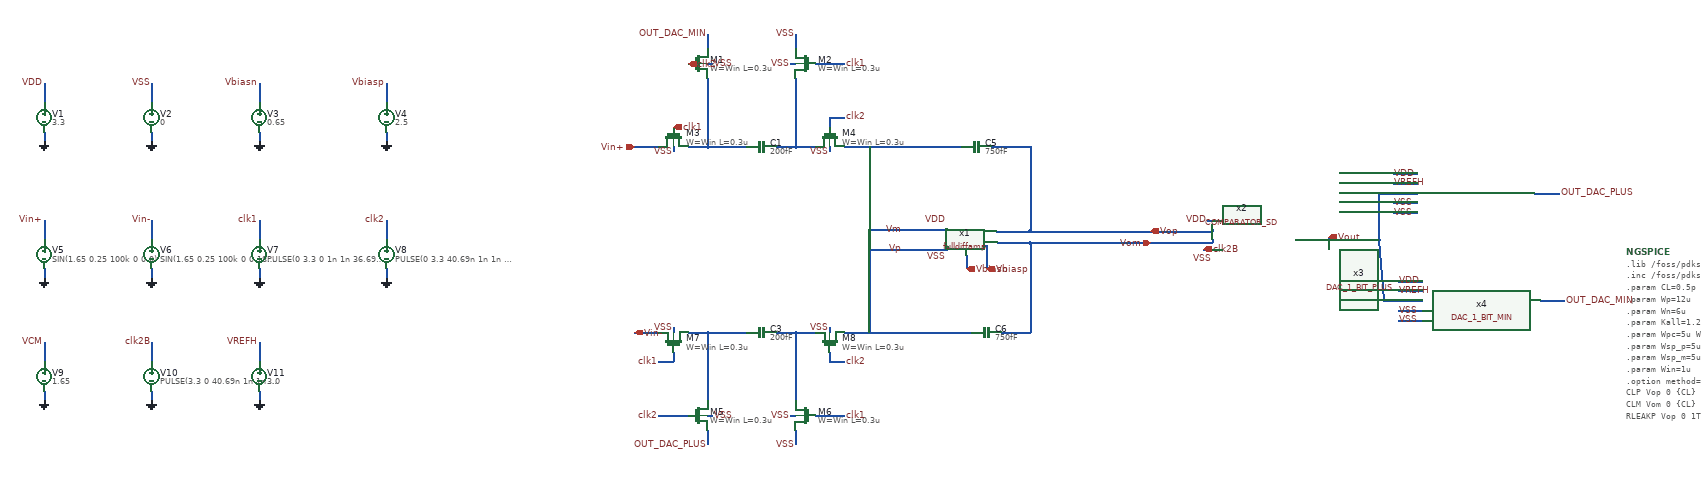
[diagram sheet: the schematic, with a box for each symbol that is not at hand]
v {xschem version=3.4.8RC file_version=1.3}
G {}
K {}
V {}
S {}
F {}
E {}
N -80 -1151.25 -80 -1011.25 {lab=#net1}
N -120 -1011.25 -80 -1011.25 {lab=#net1}
N -80 -1011.25 0 -1011.25 {lab=#net1}
N 60 -1011.25 100 -1011.25 {lab=#net2}
N 100 -1151.25 100 -1011.25 {lab=#net2}
N 100 -1011.25 140 -1011.25 {lab=#net2}
N 200 -1011.25 240 -1011.25 {lab=Vm}
N -200 -1011.25 -180 -1011.25 {lab=Vin+}
N -230 -1011.25 -200 -1011.25 {lab=Vin+}
N 170 -1071.25 170 -1051.25 {lab=clk2}
N 170 -1071.25 200 -1071.25 {lab=clk2}
N 140 -1181.25 200 -1181.25 {lab=clk1}
N 100 -1241.25 100 -1211.25 {lab=VSS}
N -80 -1241.25 -80 -1211.25 {lab=OUT_DAC_MIN}
N -80 -631.25 -80 -491.25 {lab=#net3}
N -120 -631.25 -80 -631.25 {lab=#net3}
N -80 -631.25 0 -631.25 {lab=#net3}
N 60 -631.25 100 -631.25 {lab=#net4}
N 100 -631.25 100 -491.25 {lab=#net4}
N 100 -631.25 140 -631.25 {lab=#net4}
N 200 -631.25 240 -631.25 {lab=Vp}
N -200 -631.25 -180 -631.25 {lab=Vin-}
N -230 -631.25 -200 -631.25 {lab=Vin-}
N -150 -591.25 -150 -571.25 {lab=clk1}
N -180 -571.25 -150 -571.25 {lab=clk1}
N -180 -461.25 -120 -461.25 {lab=clk2}
N 170 -591.25 170 -571.25 {lab=clk2}
N 170 -571.25 200 -571.25 {lab=clk2}
N 140 -461.25 200 -461.25 {lab=clk1}
N 100 -431.25 100 -401.25 {lab=VSS}
N -80 -431.25 -80 -401.25 {lab=OUT_DAC_PLUS}
N -80 -1181.25 -70 -1181.25 {lab=VSS}
N 90 -1181.25 100 -1181.25 {lab=VSS}
N -150 -1011.25 -150 -1001.25 {lab=VSS}
N 170 -1011.25 170 -1001.25 {lab=VSS}
N -150 -641.25 -150 -631.25 {lab=VSS}
N 170 -641.25 170 -631.25 {lab=VSS}
N -80 -461.25 -70 -461.25 {lab=VSS}
N 90 -461.25 100 -461.25 {lab=VSS}
N 240 -1011.25 440 -1011.25 {lab=Vm}
N 240 -631.25 460 -631.25 {lab=Vp}
N 250 -1011.25 250 -841.25 {lab=Vm}
N 250 -841.25 410 -841.25 {lab=Vm}
N 250 -801.25 250 -631.25 {lab=Vp}
N 250 -801.25 410 -801.25 {lab=Vp}
N 410 -806.25 410 -801.25 {lab=Vp}
N 500 -1011.25 570 -1011.25 {lab=Vop}
N 520 -631.25 580 -631.25 {lab=Vom}
N 512.5 -815 580 -815 {lab=Vom}
N 511.25 -838.75 578.75 -838.75 {lab=Vop}
N 570 -1011.25 580 -1011.25 {lab=Vop}
N 578.75 -838.75 580 -838.75 {lab=Vop}
N 580 -1011.25 580 -838.75 {lab=Vop}
N 580 -815 580 -631.25 {lab=Vom}
N 482.5 -808.75 490 -808.75 {lab=Vbiasp}
N 490 -808.75 490 -761.25 {lab=Vbiasp}
N 450 -788.75 450 -761.25 {lab=Vbiasn}
N 580 -838.75 622.5 -838.75 {lab=Vop}
N 580 -815 622.5 -815 {lab=Vom}
N 802.5 -838.75 952.5 -838.75 {lab=Vop}
N 952.5 -841.25 952.5 -838.75 {lab=Vop}
N 802.5 -815 952.5 -815 {lab=Vom}
N 952.5 -821.25 952.5 -815 {lab=Vom}
N 1122.5 -821.25 1292.5 -821.25 {lab=Vout}
N 625 -838.75 672.5 -838.75 {lab=Vop}
N 625 -815 672.5 -815 {lab=Vom}
N 622.5 -838.75 625 -838.75 {lab=Vop}
N 622.5 -815 625 -815 {lab=Vom}
N -1437.5 -1141.25 -1437.5 -1101.25 {lab=VDD}
N -1437.5 -1041.25 -1437.5 -1021.25 {lab=0}
N -1217.5 -1141.25 -1217.5 -1101.25 {lab=VSS}
N -1217.5 -1041.25 -1217.5 -1021.25 {lab=0}
N -997.5 -1141.25 -997.5 -1101.25 {lab=Vbiasn}
N -997.5 -1041.25 -997.5 -1021.25 {lab=0}
N -737.5 -1141.25 -737.5 -1101.25 {lab=Vbiasp}
N -737.5 -1041.25 -737.5 -1021.25 {lab=0}
N -1437.5 -861.25 -1437.5 -821.25 {lab=Vin+}
N -1437.5 -761.25 -1437.5 -741.25 {lab=0}
N -1217.5 -861.25 -1217.5 -821.25 {lab=Vin-}
N -1217.5 -761.25 -1217.5 -741.25 {lab=0}
N -997.5 -861.25 -997.5 -821.25 {lab=clk1}
N -997.5 -761.25 -997.5 -741.25 {lab=0}
N -737.5 -861.25 -737.5 -821.25 {lab=clk2}
N -737.5 -761.25 -737.5 -741.25 {lab=0}
N -1437.5 -611.25 -1437.5 -571.25 {lab=VCM}
N -1437.5 -511.25 -1437.5 -491.25 {lab=0}
N -1217.5 -611.25 -1217.5 -571.25 {lab=clk2B}
N -1217.5 -511.25 -1217.5 -491.25 {lab=0}
N 672.5 -838.75 802.5 -838.75 {lab=Vop}
N 672.5 -815 802.5 -815 {lab=Vom}
N 933.4375 -801.5625 952.5 -801.25 {lab=clk2B}
N 942.1875 -861.25 952.5 -861.25 {lab=VDD}
N 1190 -826.25 1190 -821.25 {lab=Vout}
N 1322.5 -896.25 1372.5 -896.25 {lab=VSS}
N 1292.5 -916.25 1372.5 -916.25 {lab=Vout}
N 1322.5 -956.25 1372.5 -956.25 {lab=VDD}
N 1292.5 -916.25 1292.5 -821.25 {lab=Vout}
N 1322.5 -876.25 1372.5 -876.25 {lab=VSS}
N 1322.5 -936.25 1372.5 -936.25 {lab=VREFH}
N 1611.25 -916.25 1662.5 -916.25 {lab=OUT_DAC_PLUS}
N 1332.5 -736.25 1382.5 -736.25 {lab=VDD}
N 1332.5 -716.25 1382.5 -716.25 {lab=VREFH}
N 1302.5 -696.25 1382.5 -696.25 {lab=Vout}
N 1332.5 -676.25 1382.5 -676.25 {lab=VSS}
N 1332.5 -656.25 1382.5 -656.25 {lab=VSS}
N 1622.5 -696.25 1672.5 -696.25 {lab=OUT_DAC_MIN}
N -997.5 -611.25 -997.5 -571.25 {lab=VREFH}
N -997.5 -511.25 -997.5 -491.25 {lab=0}
N 1292.5 -821.25 1302.5 -696.25 {lab=Vout}
C {symbols/nfet_03v3.sym} -100 -1181.25 2 1 {name=M1
L=0.3u
W=Win
nf=1
m=1
ad="'int((nf+1)/2) * W/nf * 0.18u'"
pd="'2*int((nf+1)/2) * (W/nf + 0.18u)'"
as="'int((nf+2)/2) * W/nf * 0.18u'"
ps="'2*int((nf+2)/2) * (W/nf + 0.18u)'"
nrd="'0.18u / W'" nrs="'0.18u / W'"
sa=0 sb=0 sd=0
model=nfet_03v3
spiceprefix=X
}
C {symbols/nfet_03v3.sym} 120 -1181.25 2 0 {name=M2
L=0.3u
W=Win
nf=1
m=1
ad="'int((nf+1)/2) * W/nf * 0.18u'"
pd="'2*int((nf+1)/2) * (W/nf + 0.18u)'"
as="'int((nf+2)/2) * W/nf * 0.18u'"
ps="'2*int((nf+2)/2) * (W/nf + 0.18u)'"
nrd="'0.18u / W'" nrs="'0.18u / W'"
sa=0 sb=0 sd=0
model=nfet_03v3
spiceprefix=X
}
C {symbols/nfet_03v3.sym} -150 -1031.25 3 1 {name=M3
L=0.3u
W=Win
nf=1
m=1
ad="'int((nf+1)/2) * W/nf * 0.18u'"
pd="'2*int((nf+1)/2) * (W/nf + 0.18u)'"
as="'int((nf+2)/2) * W/nf * 0.18u'"
ps="'2*int((nf+2)/2) * (W/nf + 0.18u)'"
nrd="'0.18u / W'" nrs="'0.18u / W'"
sa=0 sb=0 sd=0
model=nfet_03v3
spiceprefix=X
}
C {symbols/nfet_03v3.sym} 170 -1031.25 3 1 {name=M4
L=0.3u
W=Win
nf=1
m=1
ad="'int((nf+1)/2) * W/nf * 0.18u'"
pd="'2*int((nf+1)/2) * (W/nf + 0.18u)'"
as="'int((nf+2)/2) * W/nf * 0.18u'"
ps="'2*int((nf+2)/2) * (W/nf + 0.18u)'"
nrd="'0.18u / W'" nrs="'0.18u / W'"
sa=0 sb=0 sd=0
model=nfet_03v3
spiceprefix=X
}
C {capa.sym} 30 -1011.25 1 1 {name=C1
m=1
value=200fF
footprint=1206
device="ceramic capacitor"}
C {ipin.sym} -230 -1011.25 0 0 {name=p3 lab=Vin+}
C {lab_pin.sym} 200 -1181.25 2 0 {name=p1 sig_type=std_logic lab=clk1}
C {lab_pin.sym} 200 -1071.25 2 0 {name=p5 sig_type=std_logic lab=clk2}
C {symbols/nfet_03v3.sym} -100 -461.25 0 0 {name=M5
L=0.3u
W=Win
nf=1
m=1
ad="'int((nf+1)/2) * W/nf * 0.18u'"
pd="'2*int((nf+1)/2) * (W/nf + 0.18u)'"
as="'int((nf+2)/2) * W/nf * 0.18u'"
ps="'2*int((nf+2)/2) * (W/nf + 0.18u)'"
nrd="'0.18u / W'" nrs="'0.18u / W'"
sa=0 sb=0 sd=0
model=nfet_03v3
spiceprefix=X
}
C {symbols/nfet_03v3.sym} 120 -461.25 0 1 {name=M6
L=0.3u
W=Win
nf=1
m=1
ad="'int((nf+1)/2) * W/nf * 0.18u'"
pd="'2*int((nf+1)/2) * (W/nf + 0.18u)'"
as="'int((nf+2)/2) * W/nf * 0.18u'"
ps="'2*int((nf+2)/2) * (W/nf + 0.18u)'"
nrd="'0.18u / W'" nrs="'0.18u / W'"
sa=0 sb=0 sd=0
model=nfet_03v3
spiceprefix=X
}
C {symbols/nfet_03v3.sym} -150 -611.25 3 0 {name=M7
L=0.3u
W=Win
nf=1
m=1
ad="'int((nf+1)/2) * W/nf * 0.18u'"
pd="'2*int((nf+1)/2) * (W/nf + 0.18u)'"
as="'int((nf+2)/2) * W/nf * 0.18u'"
ps="'2*int((nf+2)/2) * (W/nf + 0.18u)'"
nrd="'0.18u / W'" nrs="'0.18u / W'"
sa=0 sb=0 sd=0
model=nfet_03v3
spiceprefix=X
}
C {symbols/nfet_03v3.sym} 170 -611.25 3 0 {name=M8
L=0.3u
W=Win
nf=1
m=1
ad="'int((nf+1)/2) * W/nf * 0.18u'"
pd="'2*int((nf+1)/2) * (W/nf + 0.18u)'"
as="'int((nf+2)/2) * W/nf * 0.18u'"
ps="'2*int((nf+2)/2) * (W/nf + 0.18u)'"
nrd="'0.18u / W'" nrs="'0.18u / W'"
sa=0 sb=0 sd=0
model=nfet_03v3
spiceprefix=X
}
C {capa.sym} 30 -631.25 1 0 {name=C3
m=1
value=200fF
footprint=1206
device="ceramic capacitor"}
C {ipin.sym} -230 -631.25 2 1 {name=p6 lab=Vin-}
C {lab_pin.sym} 200 -461.25 0 1 {name=p7 sig_type=std_logic lab=clk1}
C {lab_pin.sym} -180 -571.25 2 1 {name=p8 sig_type=std_logic lab=clk1}
C {lab_pin.sym} -180 -461.25 2 1 {name=p9 sig_type=std_logic lab=clk2}
C {lab_pin.sym} 200 -571.25 0 1 {name=p10 sig_type=std_logic lab=clk2}
C {lab_pin.sym} -70 -1181.25 2 0 {name=p13 sig_type=std_logic lab=VSS}
C {lab_pin.sym} 90 -1181.25 0 0 {name=p14 sig_type=std_logic lab=VSS}
C {lab_pin.sym} -150 -1001.25 3 0 {name=p15 sig_type=std_logic lab=VSS}
C {lab_pin.sym} 170 -1001.25 3 0 {name=p16 sig_type=std_logic lab=VSS}
C {lab_pin.sym} -150 -641.25 1 0 {name=p17 sig_type=std_logic lab=VSS}
C {lab_pin.sym} 170 -641.25 1 0 {name=p18 sig_type=std_logic lab=VSS}
C {lab_pin.sym} -70 -461.25 2 0 {name=p19 sig_type=std_logic lab=VSS}
C {lab_pin.sym} 90 -461.25 0 0 {name=p20 sig_type=std_logic lab=VSS}
C {capa.sym} 470 -1011.25 3 0 {name=C5
m=1
value=750fF
footprint=1206
device="ceramic capacitor"}
C {capa.sym} 490 -631.25 3 0 {name=C6
m=1
value=750fF
footprint=1206
device="ceramic capacitor"}
C {opin.sym} 825 -838.75 3 0 {name=p11 lab=Vop}
C {opin.sym} 826.25 -815 3 1 {name=p12 lab=Vom}
C {lab_pin.sym} 410 -786.25 0 0 {name=p23 sig_type=std_logic lab=VSS}
C {lab_pin.sym} 410 -861.25 0 0 {name=p24 sig_type=std_logic lab=VDD}
C {lab_pin.sym} 100 -401.25 3 0 {name=p38 sig_type=std_logic lab=VSS}
C {lab_pin.sym} 100 -1241.25 1 0 {name=p39 sig_type=std_logic lab=VSS}
C {ipin.sym} -150 -1051.25 3 1 {name=p41 lab=clk1}
C {ipin.sym} -120 -1181.25 2 1 {name=p2 lab=clk2}
C {ipin.sym} 450 -761.25 1 1 {name=p4 lab=Vbiasn}
C {ipin.sym} 490 -761.25 1 1 {name=p42 lab=Vbiasp}
C {lab_pin.sym} 320 -841.25 1 0 {name=p33 sig_type=std_logic lab=Vm}
C {lab_pin.sym} 320 -801.25 3 0 {name=p34 sig_type=std_logic lab=Vp}
C {fulldiffamp.sym} 470 -736.25 0 0 {name=x1}
C {lab_pin.sym} 942.1875 -861.25 0 0 {name=p46 sig_type=std_logic lab=VDD}
C {lab_pin.sym} 952.5 -781.25 0 0 {name=p47 sig_type=std_logic lab=VSS}
C {ipin.sym} 933.4375 -801.5625 2 1 {name=p57 lab=clk2B}
C {lab_pin.sym} -80 -1241.25 1 0 {name=p36 sig_type=std_logic lab=OUT_DAC_MIN}
C {lab_pin.sym} -80 -401.25 3 0 {name=p21 sig_type=std_logic lab=OUT_DAC_PLUS}
C {vsource.sym} -1437.5 -1071.25 0 0 {name=V1 value=3.3 savecurrent=false}
C {gnd.sym} -1437.5 -1021.25 0 0 {name=l5 lab=0}
C {vsource.sym} -1217.5 -1071.25 0 0 {name=V2 value=0 savecurrent=false}
C {gnd.sym} -1217.5 -1021.25 0 0 {name=l6 lab=0}
C {vsource.sym} -997.5 -1071.25 0 0 {name=V3 value=0.65 savecurrent=false}
C {gnd.sym} -997.5 -1021.25 0 0 {name=l7 lab=0}
C {vsource.sym} -737.5 -1071.25 0 0 {name=V4 value=2.5 savecurrent=false}
C {gnd.sym} -737.5 -1021.25 0 0 {name=l8 lab=0}
C {vsource.sym} -1437.5 -791.25 0 0 {name=V5 value="SIN(1.65 0.25 100k 0 0 0)" savecurrent=false}
C {gnd.sym} -1437.5 -741.25 0 0 {name=l9 lab=0}
C {vsource.sym} -1217.5 -791.25 0 0 {name=V6 value="SIN(1.65 0.25 100k 0 0 180)" savecurrent=false}
C {gnd.sym} -1217.5 -741.25 0 0 {name=l10 lab=0}
C {vsource.sym} -997.5 -791.25 0 0 {name=V7 value="PULSE(0 3.3 0 1n 1n 36.69n 81.38n)" savecurrent=false}
C {gnd.sym} -997.5 -741.25 0 0 {name=l11 lab=0}
C {vsource.sym} -737.5 -791.25 0 0 {name=V8 value="PULSE(0 3.3 40.69n 1n 1n 36.69n 81.38n)" savecurrent=false}
C {gnd.sym} -737.5 -741.25 0 0 {name=l12 lab=0}
C {lab_pin.sym} -1437.5 -1141.25 1 0 {name=p25 sig_type=std_logic lab=VDD}
C {lab_pin.sym} -1217.5 -1141.25 1 0 {name=p26 sig_type=std_logic lab=VSS
}
C {lab_pin.sym} -997.5 -1141.25 1 0 {name=p27 sig_type=std_logic lab=Vbiasn
}
C {lab_pin.sym} -737.5 -1141.25 1 0 {name=p28 sig_type=std_logic lab=Vbiasp
}
C {lab_pin.sym} -1437.5 -861.25 1 0 {name=p29 sig_type=std_logic lab=Vin+}
C {lab_pin.sym} -1217.5 -861.25 1 0 {name=p30 sig_type=std_logic lab=Vin-}
C {lab_pin.sym} -997.5 -861.25 1 0 {name=p31 sig_type=std_logic lab=clk1}
C {lab_pin.sym} -737.5 -861.25 1 0 {name=p32 sig_type=std_logic lab=clk2}
C {vsource.sym} -1437.5 -541.25 0 0 {name=V9 value=1.65 savecurrent=false}
C {gnd.sym} -1437.5 -491.25 0 0 {name=l1 lab=0}
C {lab_pin.sym} -1437.5 -611.25 1 0 {name=p35 sig_type=std_logic lab=VCM}
C {devices/code_shown.sym} 1799.375 -795.625 0 0 {name=NGSPICE only_toplevel=true
value="
.lib /foss/pdks/gf180mcuD/libs.tech/ngspice/sm141064.ngspice typical
.inc /foss/pdks/gf180mcuD/libs.tech/ngspice/design.ngspice

.param CL=0.5p
.param Wp=12u
.param Wn=6u
.param Kall=1.28u
.param Wpc=5u Wnc=2.5u Wsc=2*Wp Lc=0.3u
.param Wsp_p=5u Wsn_p=0.3u Ld=0.3u Wdp_p=40u Wdn_p=0.6u Wsp2_p=5u Wsn2_p=0.3u
.param Wsp_m=5u Wsn_m=0.5u Wdp_m=10u Wdn_m=1u

.param Win=1u
.option method=gear maxord=2 reltol=1e-4
CLP Vop 0 \{CL\}
CLM Vom 0 \{CL\}
RLEAKP Vop 0 1T
RLEAKM Vom 0 1T

* dummy load supaya tiap node punya DC path ke ground
Rd1 clk1  0 1meg
Rd2 clk2  0 1meg

.control
save all
set color0=white
set color1=black
tran 10n 50u 0 2n
let vicm_ota = (v(Vp)+v(Vm))/2
let vid_ota  = v(Vp)-v(Vm)
let vod = v(Vop)-v(Vom)
let vocm = (v(Vop)+v(Vom))/2
let bit_norm = v(Vout)/3.3
plot v(Vin+) v(Vin-) v(Vout)
plot vod v(Vout)
plot v(OUT_DAC_PLUS) v(OUT_DAC_MIN)
plot vocm
write analog_integration_v15_sigma_delta.raw v(Vin+) v(Vin-) v(Vp) v(Vm) v(Vop) v(Vom) v(Vout) v(OUT_DAC_PLUS) v(OUT_DAC_MIN) v(clk1) v(clk2) v(clk2B)
let inst_pwr = -v(vdd) * i(v1)
meas tran avg_power AVG inst_pwr from=0.5m to=2m
meas tran duty_avg AVG bit_norm from=0.5m to=2m
.endc
.end
"}
C {vsource.sym} -1217.5 -541.25 0 0 {name=V10 value="PULSE(3.3 0 40.69n 1n 1n 36.69n 81.38n)" savecurrent=false}
C {gnd.sym} -1217.5 -491.25 0 0 {name=l2 lab=0}
C {lab_pin.sym} -1217.5 -611.25 1 0 {name=p22 sig_type=std_logic lab=clk2B}
C {/foss/designs/low-power-12b-first-order-delta-sigma-adc/src/schematics/latched_comparator/COMPARATOR_SD.sym} 932.5 -661.25 0 0 {name=x2}
C {opin.sym} 1190 -826.25 3 0 {name=p52 lab=Vout}
C {lab_pin.sym} 1322.5 -956.25 2 0 {name=p40 sig_type=std_logic lab=VDD}
C {lab_pin.sym} 1322.5 -936.25 2 0 {name=p58 sig_type=std_logic lab=VREFH}
C {lab_pin.sym} 1322.5 -896.25 2 0 {name=p59 sig_type=std_logic lab=VSS}
C {lab_pin.sym} 1322.5 -876.25 2 0 {name=p60 sig_type=std_logic lab=VSS}
C {lab_pin.sym} 1662.5 -916.25 2 0 {name=p61 sig_type=std_logic lab=OUT_DAC_PLUS}
C {/foss/designs/low-power-12b-first-order-delta-sigma-adc/src/schematics/dac_1bit/DAC_1_BIT_PLUS.sym} 1342.5 -826.25 0 0 {name=x3}
C {lab_pin.sym} 1332.5 -736.25 2 0 {name=p62 sig_type=std_logic lab=VDD}
C {lab_pin.sym} 1332.5 -716.25 2 0 {name=p63 sig_type=std_logic lab=VREFH}
C {lab_pin.sym} 1332.5 -676.25 2 0 {name=p64 sig_type=std_logic lab=VSS}
C {lab_pin.sym} 1332.5 -656.25 2 0 {name=p65 sig_type=std_logic lab=VSS}
C {lab_pin.sym} 1672.5 -696.25 2 0 {name=p66 sig_type=std_logic lab=OUT_DAC_MIN}
C {/foss/designs/low-power-12b-first-order-delta-sigma-adc/src/schematics/dac_1bit/DAC_1_BIT_MIN.sym} 1472.5 -566.25 0 0 {name=x4}
C {vsource.sym} -997.5 -541.25 0 0 {name=V11 value=3.0 savecurrent=false}
C {gnd.sym} -997.5 -491.25 0 0 {name=l3 lab=0}
C {lab_pin.sym} -997.5 -611.25 1 0 {name=p67 sig_type=std_logic lab=VREFH}
